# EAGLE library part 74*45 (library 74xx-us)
BCD to decimal DECODER/DRIVER

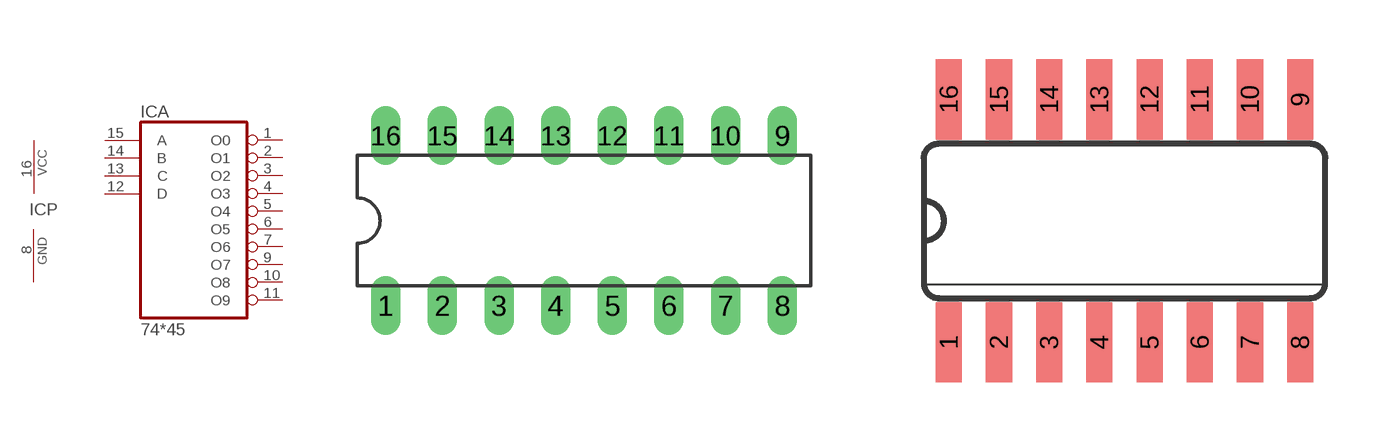
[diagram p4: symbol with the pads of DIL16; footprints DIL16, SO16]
Designator prefix IC; gates A=7445 P=PWRN

## 7445N  [DIL16]
1  A:O0  oc
2  A:O1  oc
3  A:O2  oc
4  A:O3  oc
5  A:O4  oc
6  A:O5  oc
7  A:O6  oc
8  P:GND  pwr
9  A:O7  oc
10  A:O8  oc
11  A:O9  oc
12  A:D  in
13  A:C  in
14  A:B  in
15  A:A  in
16  P:VCC  pwr

## 7445D  [SO16]
Pads as for DIL16

## Footprint DIL16 (pad centres in mm)
Dual In Line Package
drill 0.813 long: 1 -8.89,-3.81; 2 -6.35,-3.81; 3 -3.81,-3.81; 4 -1.27,-3.81; 5 1.27,-3.81; 6 3.81,-3.81; 7 6.35,-3.81; 8 8.89,-3.81; 9 8.89,3.81; 10 6.35,3.81; 11 3.81,3.81; 12 1.27,3.81; 13 -1.27,3.81; 14 -3.81,3.81; 15 -6.35,3.81; 16 -8.89,3.81

## Footprint SO16 (pad centres in mm)
Small Outline package 150 mil
smd 0.66 x 2.032: 1 -4.445,-3.073; 2 -3.175,-3.073; 3 -1.905,-3.073; 4 -0.635,-3.073; 5 0.635,-3.073; 6 1.905,-3.073; 7 3.175,-3.073; 8 4.445,-3.073; 9 4.445,3.073; 10 3.175,3.073; 11 1.905,3.073; 12 0.635,3.073; 13 -0.635,3.073; 14 -1.905,3.073; 15 -3.175,3.073; 16 -4.445,3.073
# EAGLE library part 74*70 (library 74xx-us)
AND gated J-K positive edge triggered FLIP FLOP, preset and clear

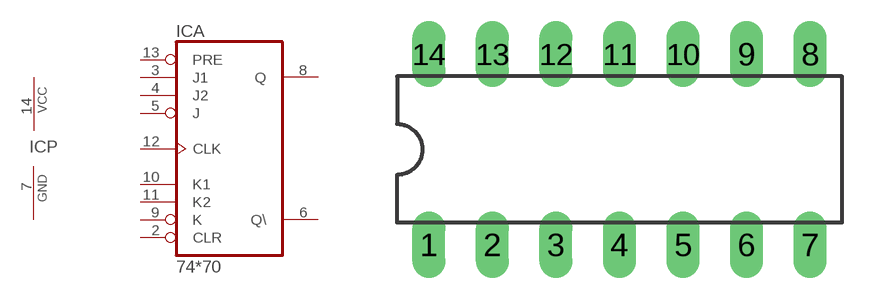
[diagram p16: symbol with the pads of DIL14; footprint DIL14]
Designator prefix IC; gates A=7470 P=PWRN

## 7470N  [DIL14]
2  A:CLR  in
3  A:J1  in
4  A:J2  in
5  A:J  in
6  A:Q\  out
7  P:GND  pwr
8  A:Q  out
9  A:K  in
10  A:K1  in
11  A:K2  in
12  A:CLK  in
13  A:PRE  in
14  P:VCC  pwr

## Footprint DIL14 (pad centres in mm)
Dual In Line Package
drill 0.813 long: 1 -7.62,-3.81; 2 -5.08,-3.81; 3 -2.54,-3.81; 4 0,-3.81; 5 2.54,-3.81; 6 5.08,-3.81; 7 7.62,-3.81; 8 7.62,3.81; 9 5.08,3.81; 10 2.54,3.81; 11 0,3.81; 12 -2.54,3.81; 13 -5.08,3.81; 14 -7.62,3.81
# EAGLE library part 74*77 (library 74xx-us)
4-bit D LATCH

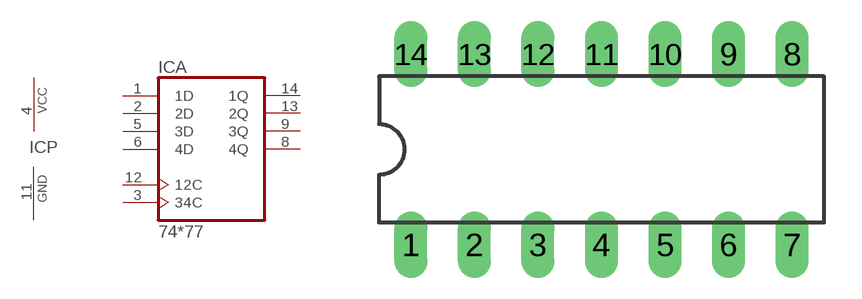
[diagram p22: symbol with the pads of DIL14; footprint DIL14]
Designator prefix IC; gates A=7477 P=PWRN

## 7477N  [DIL14]
1  A:1D  in
2  A:2D  in
3  A:34C  in
4  P:VCC  pwr
5  A:3D  in
6  A:4D  in
8  A:4Q  out
9  A:3Q  out
11  P:GND  pwr
12  A:12C  in
13  A:2Q  out
14  A:1Q  out

## Footprint DIL14 (pad centres in mm)
Dual In Line Package
drill 0.813 long: 1 -7.62,-3.81; 2 -5.08,-3.81; 3 -2.54,-3.81; 4 0,-3.81; 5 2.54,-3.81; 6 5.08,-3.81; 7 7.62,-3.81; 8 7.62,3.81; 9 5.08,3.81; 10 2.54,3.81; 11 0,3.81; 12 -2.54,3.81; 13 -5.08,3.81; 14 -7.62,3.81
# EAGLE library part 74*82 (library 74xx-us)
2-bit binary full ADDER

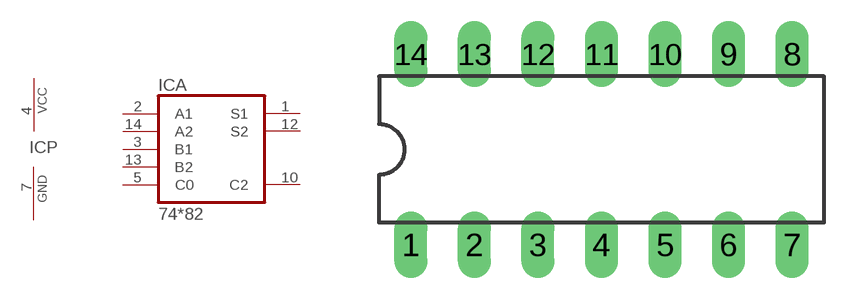
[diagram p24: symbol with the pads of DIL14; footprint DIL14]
Designator prefix IC; gates A=7482 P=PWRN

## 7482N  [DIL14]
1  A:S1  out
2  A:A1  in
3  A:B1  in
4  P:VCC  pwr
5  A:C0  in
7  P:GND  pwr
10  A:C2  out
12  A:S2  out
13  A:B2  in
14  A:A2  in

## Footprint DIL14 (pad centres in mm)
Dual In Line Package
drill 0.813 long: 1 -7.62,-3.81; 2 -5.08,-3.81; 3 -2.54,-3.81; 4 0,-3.81; 5 2.54,-3.81; 6 5.08,-3.81; 7 7.62,-3.81; 8 7.62,3.81; 9 5.08,3.81; 10 2.54,3.81; 11 0,3.81; 12 -2.54,3.81; 13 -5.08,3.81; 14 -7.62,3.81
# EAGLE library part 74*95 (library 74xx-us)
4-bit parallel access SHIFT REGISTER

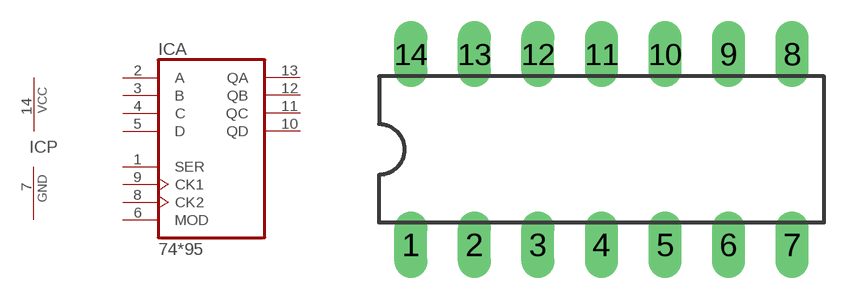
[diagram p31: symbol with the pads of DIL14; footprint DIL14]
Designator prefix IC; gates A=7495 P=PWRN

## 7495N, 74LS95N  [DIL14]
1  A:SER  in
2  A:A  in
3  A:B  in
4  A:C  in
5  A:D  in
6  A:MOD  in
7  P:GND  pwr
8  A:CK2  in
9  A:CK1  in
10  A:QD  out
11  A:QC  out
12  A:QB  out
13  A:QA  out
14  P:VCC  pwr

## Footprint DIL14 (pad centres in mm)
Dual In Line Package
drill 0.813 long: 1 -7.62,-3.81; 2 -5.08,-3.81; 3 -2.54,-3.81; 4 0,-3.81; 5 2.54,-3.81; 6 5.08,-3.81; 7 7.62,-3.81; 8 7.62,3.81; 9 5.08,3.81; 10 2.54,3.81; 11 0,3.81; 12 -2.54,3.81; 13 -5.08,3.81; 14 -7.62,3.81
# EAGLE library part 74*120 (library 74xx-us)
Dual pulse SYNCHRONIZER/DRIVER

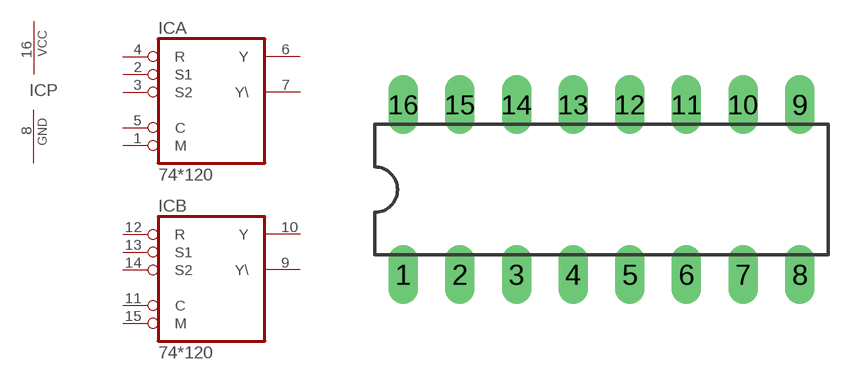
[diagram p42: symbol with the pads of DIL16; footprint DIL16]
Designator prefix IC; gates A=74120 B=74120 P=PWRN

## 74120N  [DIL16]
1  A:M  in
2  A:S1  in
3  A:S2  in
4  A:R  in
5  A:C  in
6  A:Y  out
7  A:Y\  out
8  P:GND  pwr
9  B:Y\  out
10  B:Y  out
11  B:C  in
12  B:R  in
13  B:S1  in
14  B:S2  in
15  B:M  in
16  P:VCC  pwr

## Footprint DIL16 (pad centres in mm)
Dual In Line Package
drill 0.813 long: 1 -8.89,-3.81; 2 -6.35,-3.81; 3 -3.81,-3.81; 4 -1.27,-3.81; 5 1.27,-3.81; 6 3.81,-3.81; 7 6.35,-3.81; 8 8.89,-3.81; 9 8.89,3.81; 10 6.35,3.81; 11 3.81,3.81; 12 1.27,3.81; 13 -1.27,3.81; 14 -3.81,3.81; 15 -6.35,3.81; 16 -8.89,3.81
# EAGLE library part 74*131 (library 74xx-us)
3-line to 8-line DECODER/DEMULTIPLEXER, address register

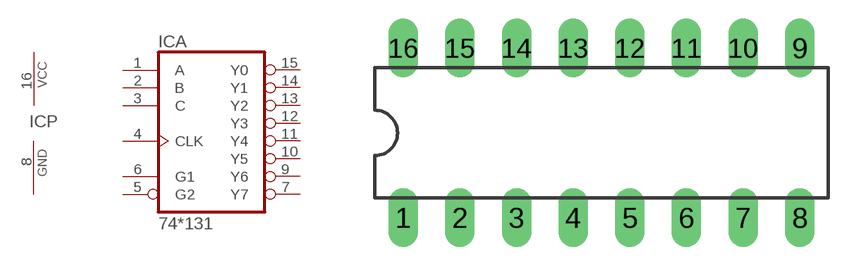
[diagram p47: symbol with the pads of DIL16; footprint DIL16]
Designator prefix IC; gates A=74131 P=PWRN

## 74131N  [DIL16]
1  A:A  in
2  A:B  in
3  A:C  in
4  A:CLK  in
5  A:G2  in
6  A:G1  in
7  A:Y7  out
8  P:GND  pwr
9  A:Y6  out
10  A:Y5  out
11  A:Y4  out
12  A:Y3  out
13  A:Y2  out
14  A:Y1  out
15  A:Y0  out
16  P:VCC  pwr

## Footprint DIL16 (pad centres in mm)
Dual In Line Package
drill 0.813 long: 1 -8.89,-3.81; 2 -6.35,-3.81; 3 -3.81,-3.81; 4 -1.27,-3.81; 5 1.27,-3.81; 6 3.81,-3.81; 7 6.35,-3.81; 8 8.89,-3.81; 9 8.89,3.81; 10 6.35,3.81; 11 3.81,3.81; 12 1.27,3.81; 13 -1.27,3.81; 14 -3.81,3.81; 15 -6.35,3.81; 16 -8.89,3.81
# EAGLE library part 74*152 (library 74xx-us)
Data SELECTOR/MULTIPLEXER

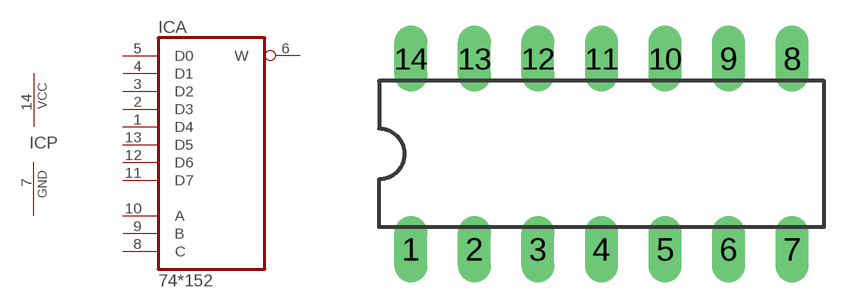
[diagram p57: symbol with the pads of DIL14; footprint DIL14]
Designator prefix IC; gates A=74152 P=PWRN

## 74LS152N  [DIL14]
1  A:D4  in
2  A:D3  in
3  A:D2  in
4  A:D1  in
5  A:D0  in
6  A:W  out
7  P:GND  pwr
8  A:C  in
9  A:B  in
10  A:A  in
11  A:D7  in
12  A:D6  in
13  A:D5  in
14  P:VCC  pwr

## Footprint DIL14 (pad centres in mm)
Dual In Line Package
drill 0.813 long: 1 -7.62,-3.81; 2 -5.08,-3.81; 3 -2.54,-3.81; 4 0,-3.81; 5 2.54,-3.81; 6 5.08,-3.81; 7 7.62,-3.81; 8 7.62,3.81; 9 5.08,3.81; 10 2.54,3.81; 11 0,3.81; 12 -2.54,3.81; 13 -5.08,3.81; 14 -7.62,3.81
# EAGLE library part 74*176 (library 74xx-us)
Presettable decade/binary COUNTER/LATCH

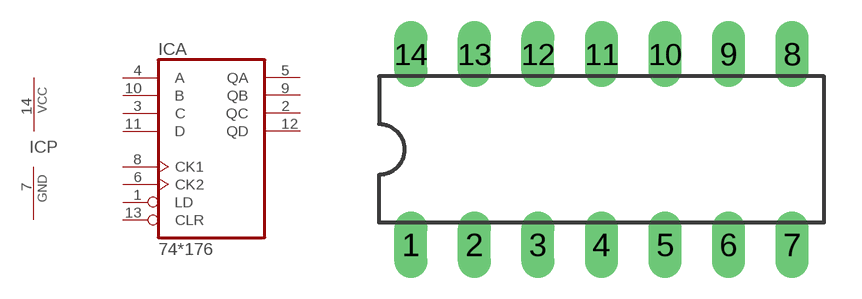
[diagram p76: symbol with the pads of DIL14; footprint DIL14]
Designator prefix IC; gates A=74176 P=PWRN

## 74176N  [DIL14]
1  A:LD  in
2  A:QC  out
3  A:C  in
4  A:A  in
5  A:QA  out
6  A:CK2  in
7  P:GND  pwr
8  A:CK1  in
9  A:QB  out
10  A:B  in
11  A:D  in
12  A:QD  out
13  A:CLR  in
14  P:VCC  pwr

## Footprint DIL14 (pad centres in mm)
Dual In Line Package
drill 0.813 long: 1 -7.62,-3.81; 2 -5.08,-3.81; 3 -2.54,-3.81; 4 0,-3.81; 5 2.54,-3.81; 6 5.08,-3.81; 7 7.62,-3.81; 8 7.62,3.81; 9 5.08,3.81; 10 2.54,3.81; 11 0,3.81; 12 -2.54,3.81; 13 -5.08,3.81; 14 -7.62,3.81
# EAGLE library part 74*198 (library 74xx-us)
8-bit SHIFT REGISTER

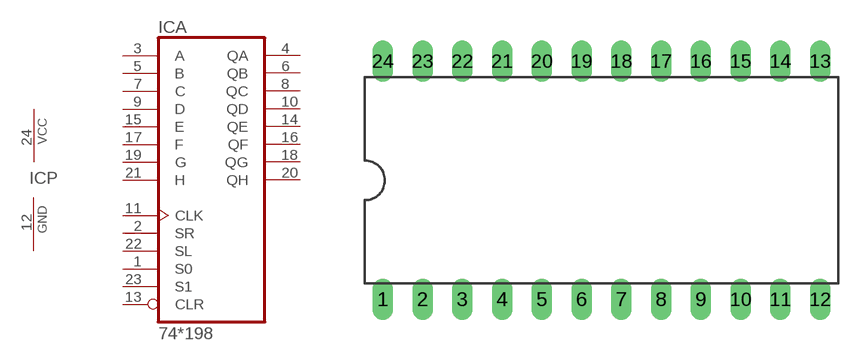
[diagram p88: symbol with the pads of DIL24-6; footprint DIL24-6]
Designator prefix IC; gates A=74198 P=PWRN

## 74198N  [DIL24-6]
1  A:S0  in
2  A:SR  in
3  A:A  in
4  A:QA  out
5  A:B  in
6  A:QB  out
7  A:C  in
8  A:QC  out
9  A:D  in
10  A:QD  out
11  A:CLK  in
12  P:GND  pwr
13  A:CLR  in
14  A:QE  out
15  A:E  in
16  A:QF  out
17  A:F  in
18  A:QG  out
19  A:G  in
20  A:QH  out
21  A:H  in
22  A:SL  in
23  A:S1  in
24  P:VCC  pwr

## Footprint DIL24-6 (pad centres in mm)
Dual In Line Package 0.6 inch
drill 0.813 long: 1 -13.97,-7.62; 2 -11.43,-7.62; 3 -8.89,-7.62; 4 -6.35,-7.62; 5 -3.81,-7.62; 6 -1.27,-7.62; 7 1.27,-7.62; 8 3.81,-7.62; 9 6.35,-7.62; 10 8.89,-7.62; 11 11.43,-7.62; 12 13.97,-7.62; 13 13.97,7.62; 14 11.43,7.62; 15 8.89,7.62; 16 6.35,7.62; 17 3.81,7.62; 18 1.27,7.62; 19 -1.27,7.62; 20 -3.81,7.62; 21 -6.35,7.62; 22 -8.89,7.62; 23 -11.43,7.62; 24 -13.97,7.62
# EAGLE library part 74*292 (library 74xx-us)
Programmable frequency DIVIDER/DIGITAL TIMER

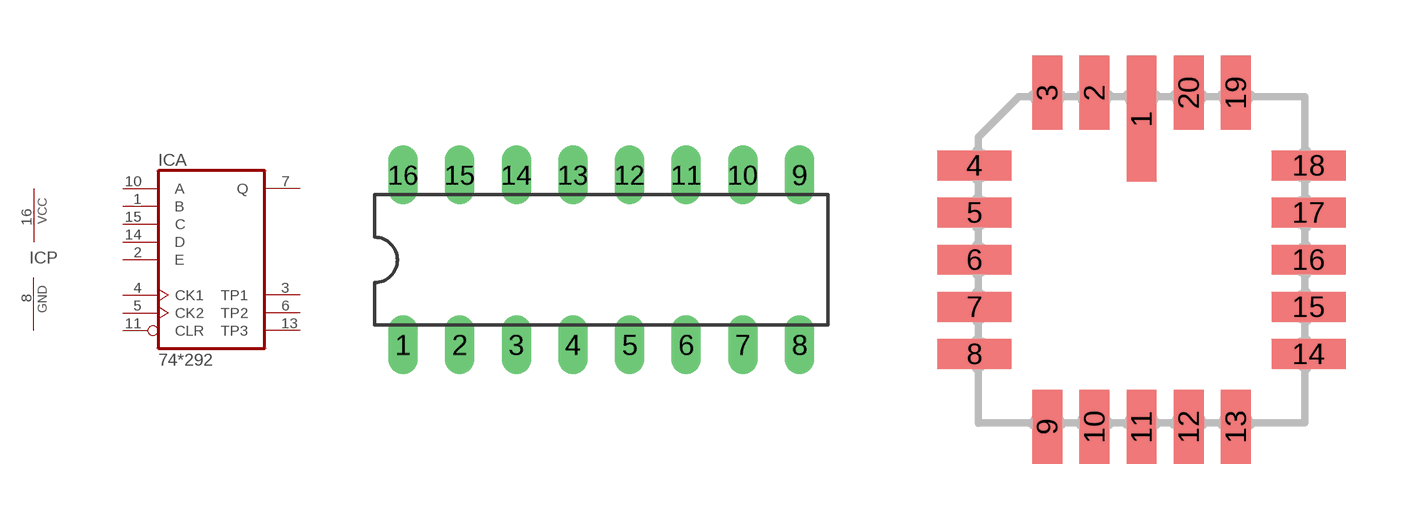
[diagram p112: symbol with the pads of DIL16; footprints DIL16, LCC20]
Designator prefix IC; gates A=74292 P=PWRN

## 74LS292N  [DIL16]
1  A:B  in
2  A:E  in
3  A:TP1  out
4  A:CK1  in
5  A:CK2  in
6  A:TP2  out
7  A:Q  out
8  P:GND  pwr
10  A:A  in
11  A:CLR  in
13  A:TP3  out
14  A:D  in
15  A:C  in
16  P:VCC  pwr

## 74LS292FK  [LCC20]
2  A:B  in
3  A:E  in
4  A:TP1  out
5  A:CK1  in
7  A:CK2  in
8  A:TP2  out
9  A:Q  out
10  P:GND  pwr
13  A:A  in
14  A:CLR  in
17  A:TP3  out
18  A:D  in
19  A:C  in
20  P:VCC  pwr

## Footprint DIL16 (pad centres in mm)
Dual In Line Package
drill 0.813 long: 1 -8.89,-3.81; 2 -6.35,-3.81; 3 -3.81,-3.81; 4 -1.27,-3.81; 5 1.27,-3.81; 6 3.81,-3.81; 7 6.35,-3.81; 8 8.89,-3.81; 9 8.89,3.81; 10 6.35,3.81; 11 3.81,3.81; 12 1.27,3.81; 13 -1.27,3.81; 14 -3.81,3.81; 15 -6.35,3.81; 16 -8.89,3.81

## Footprint LCC20 (pad centres in mm)
Leadless Chip Carrier Ceramic Package
smd 0.8 x 3.4: 1 0,3.8
smd 0.8 x 2: 2 -1.27,4.5; 3 -2.54,4.5; 9 -2.54,-4.5; 10 -1.27,-4.5; 11 0,-4.5; 12 1.27,-4.5; 13 2.54,-4.5; 19 2.54,4.5; 20 1.27,4.5
smd 2 x 0.8: 4 -4.5,2.54; 5 -4.5,1.27; 6 -4.5,0; 7 -4.5,-1.27; 8 -4.5,-2.54; 14 4.5,-2.54; 15 4.5,-1.27; 16 4.5,0; 17 4.5,1.27; 18 4.5,2.54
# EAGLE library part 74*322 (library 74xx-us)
8-bit SHIFT REGISTER

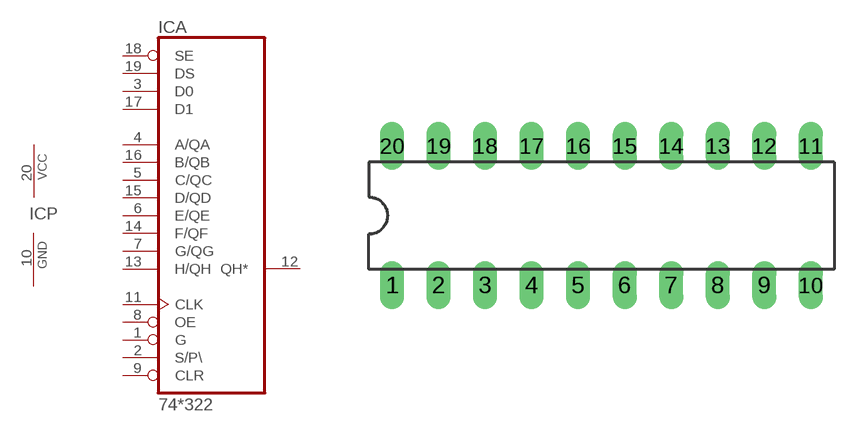
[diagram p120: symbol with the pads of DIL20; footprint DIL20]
Designator prefix IC; gates A=74322 P=PWRN

## 74322N  [DIL20]
1  A:G  in
2  A:S/P\  in
3  A:D0  in
4  A:A/QA
5  A:C/QC  in
6  A:E/QE  in
7  A:G/QG
8  A:OE  in
9  A:CLR  in
10  P:GND  pwr
11  A:CLK  in
12  A:QH*  hiz
13  A:H/QH
14  A:F/QF
15  A:D/QD  in
16  A:B/QB
17  A:D1  in
18  A:SE  in
19  A:DS  in
20  P:VCC  pwr

## Footprint DIL20 (pad centres in mm)
Dual In Line Package
drill 0.813 long: 1 -11.43,-3.81; 2 -8.89,-3.81; 3 -6.35,-3.81; 4 -3.81,-3.81; 5 -1.27,-3.81; 6 1.27,-3.81; 7 3.81,-3.81; 8 6.35,-3.81; 9 8.89,-3.81; 10 11.43,-3.81; 11 11.43,3.81; 12 8.89,3.81; 13 6.35,3.81; 14 3.81,3.81; 15 1.27,3.81; 16 -1.27,3.81; 17 -3.81,3.81; 18 -6.35,3.81; 19 -8.89,3.81; 20 -11.43,3.81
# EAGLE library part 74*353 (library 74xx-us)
Dual 4-to 1 line data SELECTOR/MULTIPLEXER, 3-state

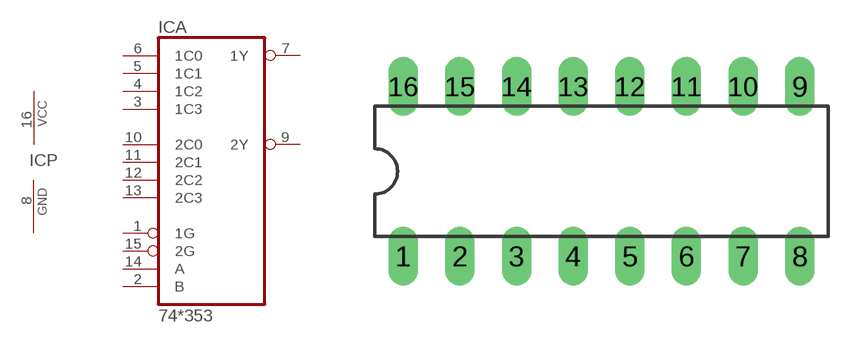
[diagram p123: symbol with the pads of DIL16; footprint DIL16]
Designator prefix IC; gates A=74353 P=PWRN

## 74353N  [DIL16]
1  A:1G  in
2  A:B  in
3  A:1C3  in
4  A:1C2  in
5  A:1C1  in
6  A:1C0  in
7  A:1Y  hiz
8  P:GND  pwr
9  A:2Y  hiz
10  A:2C0  in
11  A:2C1  in
12  A:2C2  in
13  A:2C3  in
14  A:A  in
15  A:2G  in
16  P:VCC  pwr

## Footprint DIL16 (pad centres in mm)
Dual In Line Package
drill 0.813 long: 1 -8.89,-3.81; 2 -6.35,-3.81; 3 -3.81,-3.81; 4 -1.27,-3.81; 5 1.27,-3.81; 6 3.81,-3.81; 7 6.35,-3.81; 8 8.89,-3.81; 9 8.89,3.81; 10 6.35,3.81; 11 3.81,3.81; 12 1.27,3.81; 13 -1.27,3.81; 14 -3.81,3.81; 15 -6.35,3.81; 16 -8.89,3.81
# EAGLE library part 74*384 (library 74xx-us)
8-bit by 1 twos-complement MULTIPLIER'

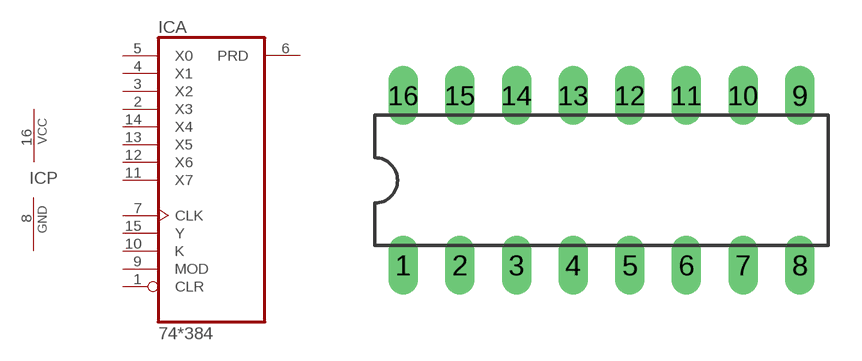
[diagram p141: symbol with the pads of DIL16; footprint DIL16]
Designator prefix IC; gates A=74384 P=PWRN

## 74384N  [DIL16]
1  A:CLR  in
2  A:X3  in
3  A:X2  in
4  A:X1  in
5  A:X0  in
6  A:PRD  out
7  A:CLK  in
8  P:GND  pwr
9  A:MOD  in
10  A:K  in
11  A:X7  in
12  A:X6  in
13  A:X5  in
14  A:X4  in
15  A:Y  in
16  P:VCC  pwr

## Footprint DIL16 (pad centres in mm)
Dual In Line Package
drill 0.813 long: 1 -8.89,-3.81; 2 -6.35,-3.81; 3 -3.81,-3.81; 4 -1.27,-3.81; 5 1.27,-3.81; 6 3.81,-3.81; 7 6.35,-3.81; 8 8.89,-3.81; 9 8.89,3.81; 10 6.35,3.81; 11 3.81,3.81; 12 1.27,3.81; 13 -1.27,3.81; 14 -3.81,3.81; 15 -6.35,3.81; 16 -8.89,3.81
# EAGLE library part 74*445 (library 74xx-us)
BCD to decimal DECODER/DRIVER

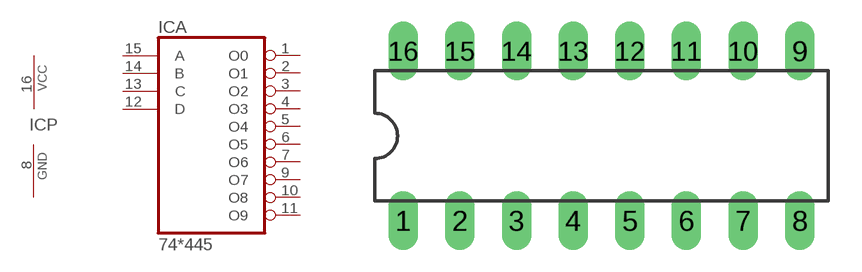
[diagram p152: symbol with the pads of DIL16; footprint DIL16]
Designator prefix IC; gates A=74445 P=PWRN

## 74445N  [DIL16]
1  A:O0  out
2  A:O1  out
3  A:O2  out
4  A:O3  out
5  A:O4  out
6  A:O5  out
7  A:O6  out
8  P:GND  pwr
9  A:O7  out
10  A:O8  out
11  A:O9  out
12  A:D  in
13  A:C  in
14  A:B  in
15  A:A  in
16  P:VCC  pwr

## Footprint DIL16 (pad centres in mm)
Dual In Line Package
drill 0.813 long: 1 -8.89,-3.81; 2 -6.35,-3.81; 3 -3.81,-3.81; 4 -1.27,-3.81; 5 1.27,-3.81; 6 3.81,-3.81; 7 6.35,-3.81; 8 8.89,-3.81; 9 8.89,3.81; 10 6.35,3.81; 11 3.81,3.81; 12 1.27,3.81; 13 -1.27,3.81; 14 -3.81,3.81; 15 -6.35,3.81; 16 -8.89,3.81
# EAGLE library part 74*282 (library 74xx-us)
LOOK AHEAD CARRY GENERATOR

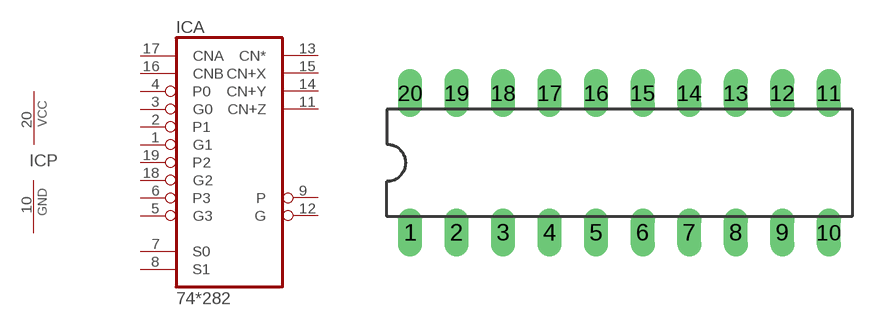
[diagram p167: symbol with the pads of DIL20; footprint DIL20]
Designator prefix IC; gates A=74282 P=PWRN

## 74AS282N  [DIL20]
1  A:G1  in
2  A:P1  in
3  A:G0  in
4  A:P0  in
5  A:G3  in
6  A:P3  in
7  A:S0  in
8  A:S1  in
9  A:P  out
10  P:GND  pwr
11  A:CN+Z  out
12  A:G  out
13  A:CN*  out
14  A:CN+Y  out
15  A:CN+X  out
16  A:CNB  in
17  A:CNA  in
18  A:G2  in
19  A:P2  in
20  P:VCC  pwr

## Footprint DIL20 (pad centres in mm)
Dual In Line Package
drill 0.813 long: 1 -11.43,-3.81; 2 -8.89,-3.81; 3 -6.35,-3.81; 4 -3.81,-3.81; 5 -1.27,-3.81; 6 1.27,-3.81; 7 3.81,-3.81; 8 6.35,-3.81; 9 8.89,-3.81; 10 11.43,-3.81; 11 11.43,3.81; 12 8.89,3.81; 13 6.35,3.81; 14 3.81,3.81; 15 1.27,3.81; 16 -1.27,3.81; 17 -3.81,3.81; 18 -6.35,3.81; 19 -8.89,3.81; 20 -11.43,3.81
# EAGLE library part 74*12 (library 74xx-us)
Triple 3-input NAND gate, open collector

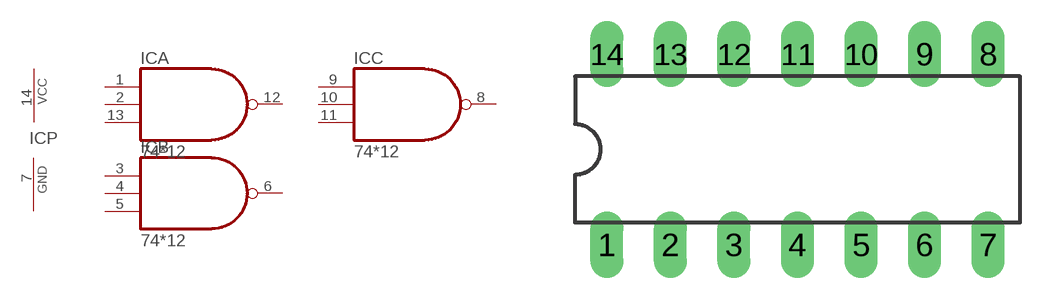
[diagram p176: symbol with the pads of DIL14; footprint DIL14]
Designator prefix IC; gates A=7412 B=7412 C=7412 P=PWRN

## 7412N, 74LS12N  [DIL14]
1  A:I0  in
2  A:I1  in
3  B:I0  in
4  B:I1  in
5  B:I2  in
6  B:O  oc
7  P:GND  pwr
8  C:O  oc
9  C:I0  in
10  C:I1  in
11  C:I2  in
12  A:O  oc
13  A:I2  in
14  P:VCC  pwr

## Footprint DIL14 (pad centres in mm)
Dual In Line Package
drill 0.813 long: 1 -7.62,-3.81; 2 -5.08,-3.81; 3 -2.54,-3.81; 4 0,-3.81; 5 2.54,-3.81; 6 5.08,-3.81; 7 7.62,-3.81; 8 7.62,3.81; 9 5.08,3.81; 10 2.54,3.81; 11 0,3.81; 12 -2.54,3.81; 13 -5.08,3.81; 14 -7.62,3.81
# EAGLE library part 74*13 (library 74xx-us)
Dual 4-input NAND schmitt trigger

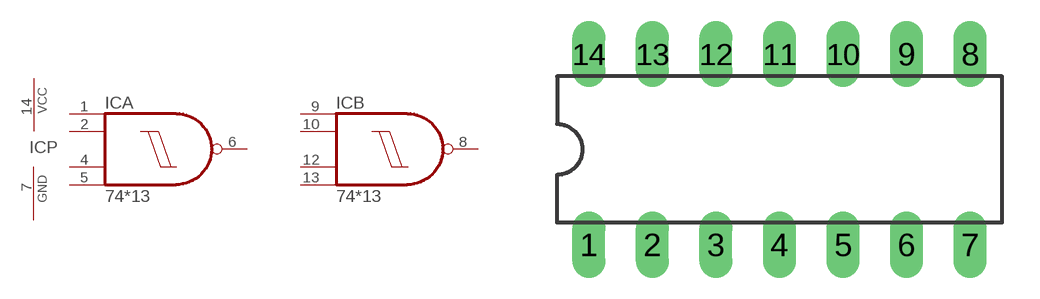
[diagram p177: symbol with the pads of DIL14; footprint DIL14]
Designator prefix IC; gates A=7413 B=7413 P=PWRN

## 7413N, 74LS13N  [DIL14]
1  A:I0  in
2  A:I1  in
4  A:I2  in
5  A:I3  in
6  A:O  out
7  P:GND  pwr
8  B:O  out
9  B:I0  in
10  B:I1  in
12  B:I2  in
13  B:I3  in
14  P:VCC  pwr

## Footprint DIL14 (pad centres in mm)
Dual In Line Package
drill 0.813 long: 1 -7.62,-3.81; 2 -5.08,-3.81; 3 -2.54,-3.81; 4 0,-3.81; 5 2.54,-3.81; 6 5.08,-3.81; 7 7.62,-3.81; 8 7.62,3.81; 9 5.08,3.81; 10 2.54,3.81; 11 0,3.81; 12 -2.54,3.81; 13 -5.08,3.81; 14 -7.62,3.81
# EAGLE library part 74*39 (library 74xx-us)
Quad 2-input NAND buffer, open collector

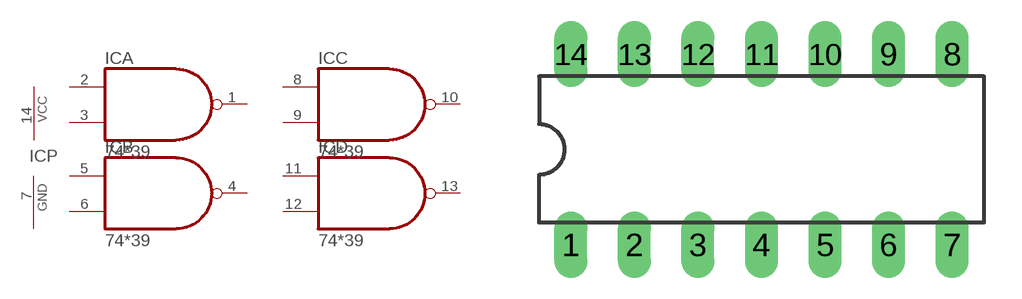
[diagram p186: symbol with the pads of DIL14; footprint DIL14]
Designator prefix IC; gates A=7439 B=7439 C=7439 D=7439 P=PWRN

## 7439N  [DIL14]
1  A:O  oc
2  A:I0  in
3  A:I1  in
4  B:O  oc
5  B:I0  in
6  B:I1  in
7  P:GND  pwr
8  C:I0  in
9  C:I1  in
10  C:O  oc
11  D:I0  in
12  D:I1  in
13  D:O  oc
14  P:VCC  pwr

## Footprint DIL14 (pad centres in mm)
Dual In Line Package
drill 0.813 long: 1 -7.62,-3.81; 2 -5.08,-3.81; 3 -2.54,-3.81; 4 0,-3.81; 5 2.54,-3.81; 6 5.08,-3.81; 7 7.62,-3.81; 8 7.62,3.81; 9 5.08,3.81; 10 2.54,3.81; 11 0,3.81; 12 -2.54,3.81; 13 -5.08,3.81; 14 -7.62,3.81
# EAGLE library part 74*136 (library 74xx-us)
Quad EXCLUSIV-OR/NOR (XOR/NOR) gate, open collector

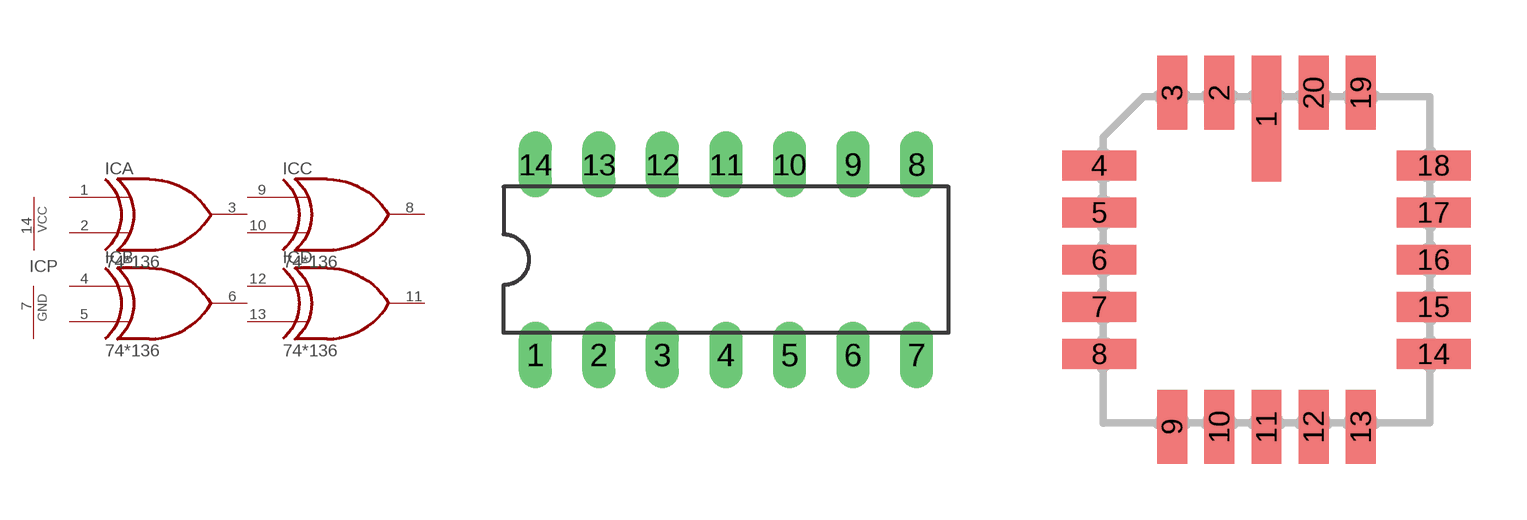
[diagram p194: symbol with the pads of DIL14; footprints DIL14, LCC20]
Designator prefix IC; gates A=74136 B=74136 C=74136 D=74136 P=PWRN

## 74LS136N  [DIL14]
1  A:I0  in
2  A:I1  in
3  A:O  oc
4  B:I0  in
5  B:I1  in
6  B:O  oc
7  P:GND  pwr
8  C:O  oc
9  C:I0  in
10  C:I1  in
11  D:O  oc
12  D:I0  in
13  D:I1  in
14  P:VCC  pwr

## 74LS136D  [DIL14]
Pads as for DIL14

## 74LS136FK  [LCC20]
2  A:I0  in
3  A:I1  in
4  A:O  oc
6  B:I0  in
8  B:I1  in
9  B:O  oc
10  P:GND  pwr
12  C:O  oc
13  C:I0  in
14  C:I1  in
16  D:O  oc
18  D:I0  in
19  D:I1  in
20  P:VCC  pwr

## Footprint DIL14 (pad centres in mm)
Dual In Line Package
drill 0.813 long: 1 -7.62,-3.81; 2 -5.08,-3.81; 3 -2.54,-3.81; 4 0,-3.81; 5 2.54,-3.81; 6 5.08,-3.81; 7 7.62,-3.81; 8 7.62,3.81; 9 5.08,3.81; 10 2.54,3.81; 11 0,3.81; 12 -2.54,3.81; 13 -5.08,3.81; 14 -7.62,3.81

## Footprint LCC20 (pad centres in mm)
Leadless Chip Carrier Ceramic Package
smd 0.8 x 3.4: 1 0,3.8
smd 0.8 x 2: 2 -1.27,4.5; 3 -2.54,4.5; 9 -2.54,-4.5; 10 -1.27,-4.5; 11 0,-4.5; 12 1.27,-4.5; 13 2.54,-4.5; 19 2.54,4.5; 20 1.27,4.5
smd 2 x 0.8: 4 -4.5,2.54; 5 -4.5,1.27; 6 -4.5,0; 7 -4.5,-1.27; 8 -4.5,-2.54; 14 4.5,-2.54; 15 4.5,-1.27; 16 4.5,0; 17 4.5,1.27; 18 4.5,2.54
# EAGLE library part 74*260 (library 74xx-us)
Dual 5-input positive NOR gate

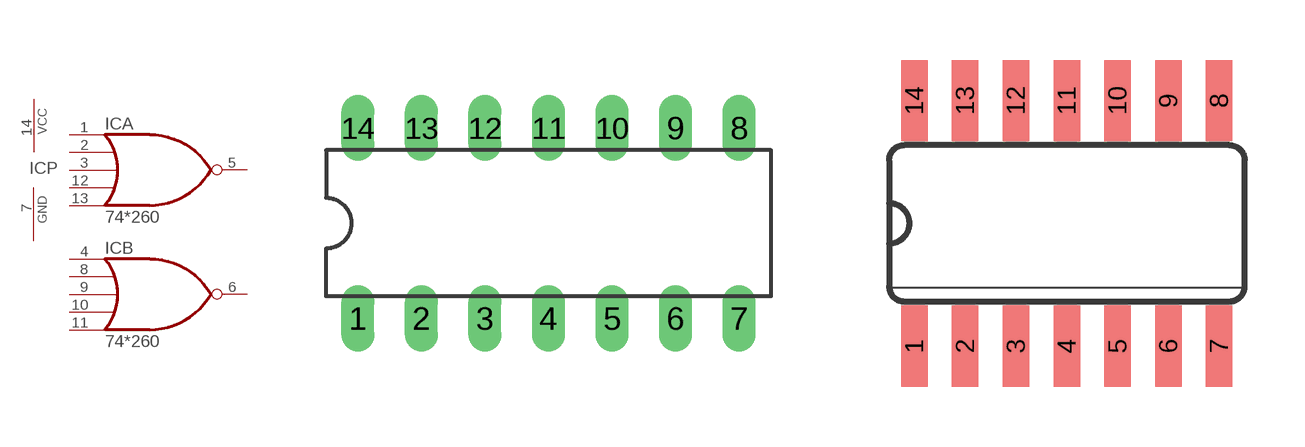
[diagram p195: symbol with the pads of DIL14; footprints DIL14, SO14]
Designator prefix IC; gates A=74260 B=74260 P=PWRN

## 74S260N  [DIL14]
1  A:I0  in
2  A:I1  in
3  A:I2  in
4  B:I0  in
5  A:O  out
6  B:O  out
7  P:GND  pwr
8  B:I1  in
9  B:I2  in
10  B:I3  in
11  B:I4  in
12  A:I3  in
13  A:I4  in
14  P:VCC  pwr

## 74S260D  [SO14]
Pads as for DIL14

## 74S260FK  [LCC20]
2  A:I0  in
3  A:I1  in
4  A:I2  in
6  B:I0  in
8  A:O  out
9  B:O  out
10  P:GND  pwr
12  B:I1  in
13  B:I2  in
14  B:I3  in
16  B:I4  in
18  A:I3  in
19  A:I4  in
20  P:VCC  pwr

## Footprint DIL14 (pad centres in mm)
Dual In Line Package
drill 0.813 long: 1 -7.62,-3.81; 2 -5.08,-3.81; 3 -2.54,-3.81; 4 0,-3.81; 5 2.54,-3.81; 6 5.08,-3.81; 7 7.62,-3.81; 8 7.62,3.81; 9 5.08,3.81; 10 2.54,3.81; 11 0,3.81; 12 -2.54,3.81; 13 -5.08,3.81; 14 -7.62,3.81

## Footprint SO14 (pad centres in mm)
Small Outline package 150 mil
smd 0.66 x 2.032: 1 -3.81,-3.073; 2 -2.54,-3.073; 3 -1.27,-3.073; 4 0,-3.073; 5 1.27,-3.073; 6 2.54,-3.073; 7 3.81,-3.073; 8 3.81,3.073; 9 2.54,3.073; 10 1.27,3.073; 11 0,3.073; 12 -1.27,3.073; 13 -2.54,3.073; 14 -3.81,3.073

## Footprint LCC20 (pad centres in mm)
Leadless Chip Carrier Ceramic Package
smd 0.8 x 3.4: 1 0,3.8
smd 0.8 x 2: 2 -1.27,4.5; 3 -2.54,4.5; 9 -2.54,-4.5; 10 -1.27,-4.5; 11 0,-4.5; 12 1.27,-4.5; 13 2.54,-4.5; 19 2.54,4.5; 20 1.27,4.5
smd 2 x 0.8: 4 -4.5,2.54; 5 -4.5,1.27; 6 -4.5,0; 7 -4.5,-1.27; 8 -4.5,-2.54; 14 4.5,-2.54; 15 4.5,-1.27; 16 4.5,0; 17 4.5,1.27; 18 4.5,2.54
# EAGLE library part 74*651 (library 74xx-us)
8-bit BUS TRANSCEIVER and REGISTER

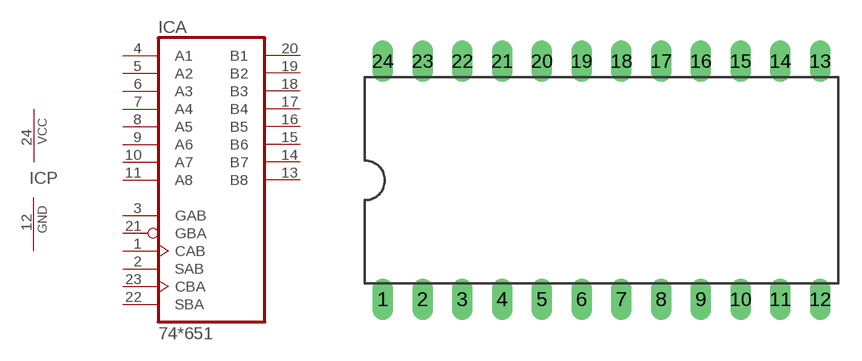
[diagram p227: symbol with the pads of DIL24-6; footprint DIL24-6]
Designator prefix IC; gates A=74651 P=PWRN

## 74AS651NT, 74LS651NT  [DIL24-6]
1  A:CAB  in
2  A:SAB  in
3  A:GAB  in
4  A:A1
5  A:A2
6  A:A3
7  A:A4
8  A:A5
9  A:A6
10  A:A7
11  A:A8
12  P:GND  pwr
13  A:B8
14  A:B7
15  A:B6
16  A:B5
17  A:B4
18  A:B3
19  A:B2
20  A:B1
21  A:GBA  in
22  A:SBA  in
23  A:CBA  in
24  P:VCC  pwr

## Footprint DIL24-6 (pad centres in mm)
Dual In Line Package 0.6 inch
drill 0.813 long: 1 -13.97,-7.62; 2 -11.43,-7.62; 3 -8.89,-7.62; 4 -6.35,-7.62; 5 -3.81,-7.62; 6 -1.27,-7.62; 7 1.27,-7.62; 8 3.81,-7.62; 9 6.35,-7.62; 10 8.89,-7.62; 11 11.43,-7.62; 12 13.97,-7.62; 13 13.97,7.62; 14 11.43,7.62; 15 8.89,7.62; 16 6.35,7.62; 17 3.81,7.62; 18 1.27,7.62; 19 -1.27,7.62; 20 -3.81,7.62; 21 -6.35,7.62; 22 -8.89,7.62; 23 -11.43,7.62; 24 -13.97,7.62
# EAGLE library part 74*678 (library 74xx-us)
16-bit address COMPARATOR, latch

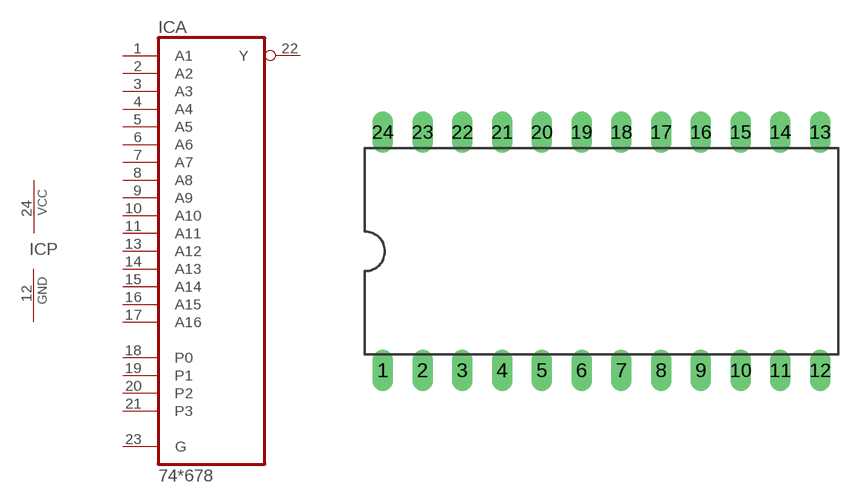
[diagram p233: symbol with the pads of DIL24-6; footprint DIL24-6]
Designator prefix IC; gates A=74678 P=PWRN

## 74ALS678NT  [DIL24-6]
1  A:A1  in
2  A:A2  in
3  A:A3  in
4  A:A4  in
5  A:A5  in
6  A:A6  in
7  A:A7  in
8  A:A8  in
9  A:A9  in
10  A:A10  in
11  A:A11  in
12  P:GND  pwr
13  A:A12  in
14  A:A13  in
15  A:A14  in
16  A:A15  in
17  A:A16  in
18  A:P0  in
19  A:P1  in
20  A:P2  in
21  A:P3  in
22  A:Y  out
23  A:G  in
24  P:VCC  pwr

## Footprint DIL24-6 (pad centres in mm)
Dual In Line Package 0.6 inch
drill 0.813 long: 1 -13.97,-7.62; 2 -11.43,-7.62; 3 -8.89,-7.62; 4 -6.35,-7.62; 5 -3.81,-7.62; 6 -1.27,-7.62; 7 1.27,-7.62; 8 3.81,-7.62; 9 6.35,-7.62; 10 8.89,-7.62; 11 11.43,-7.62; 12 13.97,-7.62; 13 13.97,7.62; 14 11.43,7.62; 15 8.89,7.62; 16 6.35,7.62; 17 3.81,7.62; 18 1.27,7.62; 19 -1.27,7.62; 20 -3.81,7.62; 21 -6.35,7.62; 22 -8.89,7.62; 23 -11.43,7.62; 24 -13.97,7.62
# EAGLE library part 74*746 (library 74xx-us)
Octal BUS DRIVER, inverting, pull-up resistors

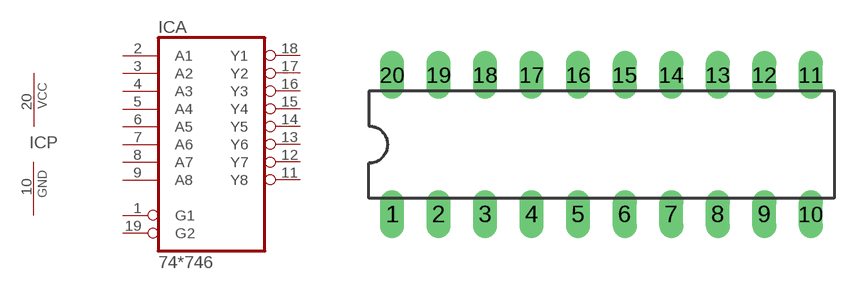
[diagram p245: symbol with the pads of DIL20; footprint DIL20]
Designator prefix IC; gates A=74746 P=PWRN

## 74ALS746N  [DIL20]
1  A:G1  in
2  A:A1  in
3  A:A2  in
4  A:A3  in
5  A:A4  in
6  A:A5  in
7  A:A6  in
8  A:A7  in
9  A:A8  in
10  P:GND  pwr
11  A:Y8  out
12  A:Y7  out
13  A:Y6  out
14  A:Y5  out
15  A:Y4  out
16  A:Y3  out
17  A:Y2  out
18  A:Y1  out
19  A:G2  in
20  P:VCC  pwr

## Footprint DIL20 (pad centres in mm)
Dual In Line Package
drill 0.813 long: 1 -11.43,-3.81; 2 -8.89,-3.81; 3 -6.35,-3.81; 4 -3.81,-3.81; 5 -1.27,-3.81; 6 1.27,-3.81; 7 3.81,-3.81; 8 6.35,-3.81; 9 8.89,-3.81; 10 11.43,-3.81; 11 11.43,3.81; 12 8.89,3.81; 13 6.35,3.81; 14 3.81,3.81; 15 1.27,3.81; 16 -1.27,3.81; 17 -3.81,3.81; 18 -6.35,3.81; 19 -8.89,3.81; 20 -11.43,3.81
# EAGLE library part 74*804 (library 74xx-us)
Hex NAND driver

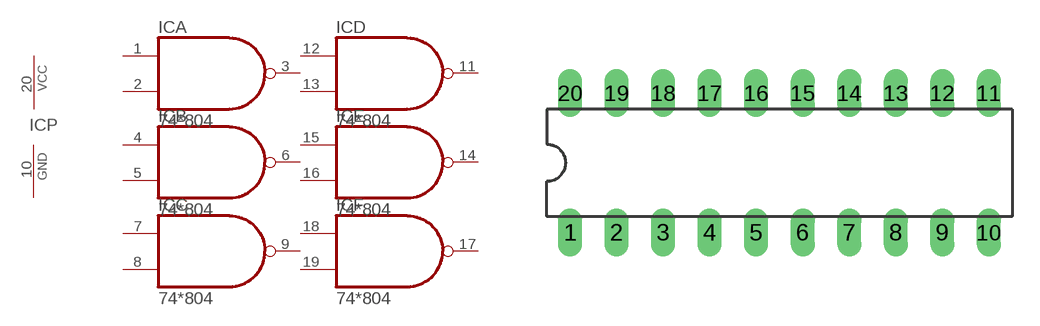
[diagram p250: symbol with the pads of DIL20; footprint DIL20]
Designator prefix IC; gates A=74804 B=74804 C=74804 D=74804 E=74804 F=74804 P=PWRN

## 74ALS804N, 74AS804N  [DIL20]
1  A:I0  in
2  A:I1  in
3  A:O  out
4  B:I0  in
5  B:I1  in
6  B:O  out
7  C:I0  in
8  C:I1  in
9  C:O  out
10  P:GND  pwr
11  D:O  out
12  D:I0  in
13  D:I1  in
14  E:O  out
15  E:I0  in
16  E:I1  in
17  F:O  out
18  F:I0  in
19  F:I1  in
20  P:VCC  pwr

## Footprint DIL20 (pad centres in mm)
Dual In Line Package
drill 0.813 long: 1 -11.43,-3.81; 2 -8.89,-3.81; 3 -6.35,-3.81; 4 -3.81,-3.81; 5 -1.27,-3.81; 6 1.27,-3.81; 7 3.81,-3.81; 8 6.35,-3.81; 9 8.89,-3.81; 10 11.43,-3.81; 11 11.43,3.81; 12 8.89,3.81; 13 6.35,3.81; 14 3.81,3.81; 15 1.27,3.81; 16 -1.27,3.81; 17 -3.81,3.81; 18 -6.35,3.81; 19 -8.89,3.81; 20 -11.43,3.81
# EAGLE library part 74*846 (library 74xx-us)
8-bit inverting bus interface LATCH

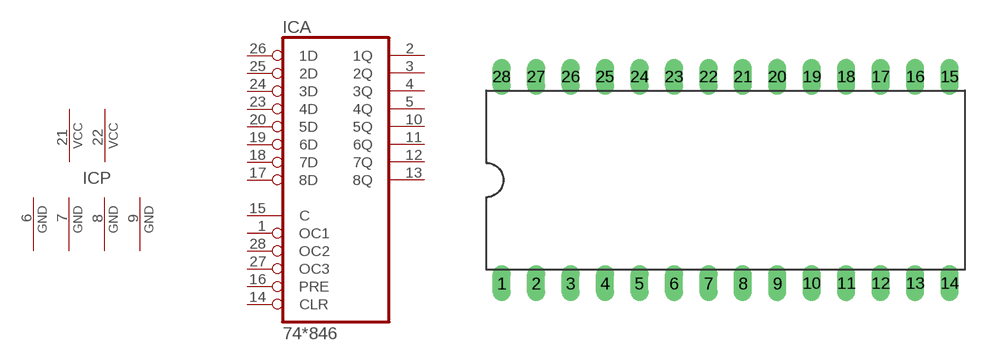
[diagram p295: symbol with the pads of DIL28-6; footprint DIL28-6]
Designator prefix IC; gates A=74846 P=2PWR4GND

## 74ALS846NT, 74AS846NT  [DIL28-6]
1  A:OC1  in
2  A:1Q  hiz
3  A:2Q  hiz
4  A:3Q  hiz
5  A:4Q  hiz
6  P:GND  pwr
7  P:GND  pwr
8  P:GND  pwr
9  P:GND  pwr
10  A:5Q  hiz
11  A:6Q  hiz
12  A:7Q  hiz
13  A:8Q  hiz
14  A:CLR  in
15  A:C  in
16  A:PRE  in
17  A:8D  in
18  A:7D  in
19  A:6D  in
20  A:5D  in
21  P:VCC  pwr
22  P:VCC  pwr
23  A:4D  in
24  A:3D  in
25  A:2D  in
26  A:1D  in
27  A:OC3  in
28  A:OC2  in

## Footprint DIL28-6 (pad centres in mm)
Dual In Line Package 0.6 inch
drill 0.813 long: 1 -16.51,-7.62; 2 -13.97,-7.62; 3 -11.43,-7.62; 4 -8.89,-7.62; 5 -6.35,-7.62; 6 -3.81,-7.62; 7 -1.27,-7.62; 8 1.27,-7.62; 9 3.81,-7.62; 10 6.35,-7.62; 11 8.89,-7.62; 12 11.43,-7.62; 13 13.97,-7.62; 14 16.51,-7.62; 15 16.51,7.62; 16 13.97,7.62; 17 11.43,7.62; 18 8.89,7.62; 19 6.35,7.62; 20 3.81,7.62; 21 1.27,7.62; 22 -1.27,7.62; 23 -3.81,7.62; 24 -6.35,7.62; 25 -8.89,7.62; 26 -11.43,7.62; 27 -13.97,7.62; 28 -16.51,7.62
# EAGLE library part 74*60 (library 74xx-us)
Dual 4-input EXPANDER

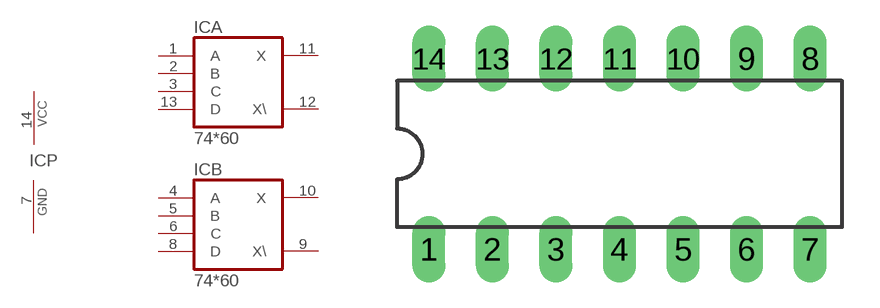
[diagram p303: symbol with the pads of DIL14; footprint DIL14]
Designator prefix IC; gates A=7460 B=7460 P=PWRN

## 7460N  [DIL14]
1  A:A  in
2  A:B  in
3  A:C  in
4  B:A  in
5  B:B  in
6  B:C  in
7  P:GND  pwr
8  B:D  in
9  B:X\  out
10  B:X  out
11  A:X  out
12  A:X\  out
13  A:D  in
14  P:VCC  pwr

## Footprint DIL14 (pad centres in mm)
Dual In Line Package
drill 0.813 long: 1 -7.62,-3.81; 2 -5.08,-3.81; 3 -2.54,-3.81; 4 0,-3.81; 5 2.54,-3.81; 6 5.08,-3.81; 7 7.62,-3.81; 8 7.62,3.81; 9 5.08,3.81; 10 2.54,3.81; 11 0,3.81; 12 -2.54,3.81; 13 -5.08,3.81; 14 -7.62,3.81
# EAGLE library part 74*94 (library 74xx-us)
4-bit SHIFT REGISTER, parallel NOR inputs, serial output

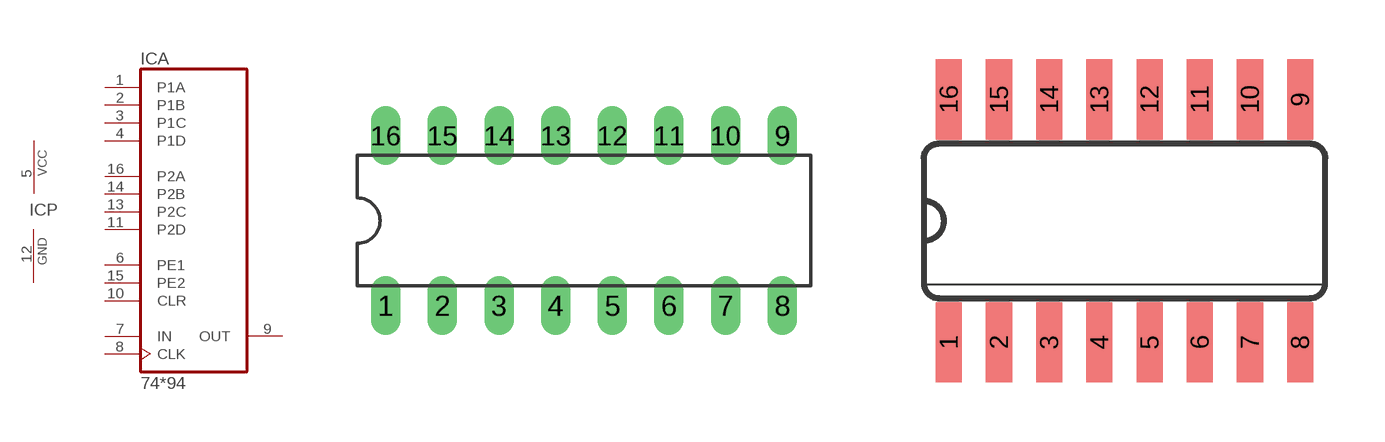
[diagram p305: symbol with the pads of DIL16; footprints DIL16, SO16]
Designator prefix IC; gates A=7494 P=PWRN

## 7494N  [DIL16]
1  A:P1A  in
2  A:P1B  in
3  A:P1C  in
4  A:P1D  in
5  P:VCC  pwr
6  A:PE1  in
7  A:IN  in
8  A:CLK  in
9  A:OUT  out
10  A:CLR  in
11  A:P2D  in
12  P:GND  pwr
13  A:P2C  in
14  A:P2B  in
15  A:PE2  in
16  A:P2A  in

## 7494J  [SO16]
Pads as for DIL16

## Footprint DIL16 (pad centres in mm)
Dual In Line Package
drill 0.813 long: 1 -8.89,-3.81; 2 -6.35,-3.81; 3 -3.81,-3.81; 4 -1.27,-3.81; 5 1.27,-3.81; 6 3.81,-3.81; 7 6.35,-3.81; 8 8.89,-3.81; 9 8.89,3.81; 10 6.35,3.81; 11 3.81,3.81; 12 1.27,3.81; 13 -1.27,3.81; 14 -3.81,3.81; 15 -6.35,3.81; 16 -8.89,3.81

## Footprint SO16 (pad centres in mm)
Small Outline package 150 mil
smd 0.66 x 2.032: 1 -4.445,-3.073; 2 -3.175,-3.073; 3 -1.905,-3.073; 4 -0.635,-3.073; 5 0.635,-3.073; 6 1.905,-3.073; 7 3.175,-3.073; 8 4.445,-3.073; 9 4.445,3.073; 10 3.175,3.073; 11 1.905,3.073; 12 0.635,3.073; 13 -0.635,3.073; 14 -1.905,3.073; 15 -3.175,3.073; 16 -4.445,3.073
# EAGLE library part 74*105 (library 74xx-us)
Single J-K FLIP FLOP

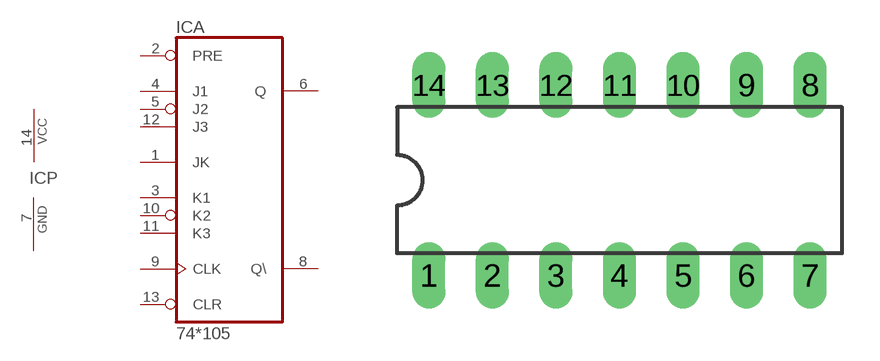
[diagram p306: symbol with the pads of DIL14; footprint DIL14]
Designator prefix IC; gates A=74105 P=PWRN

## 74105N  [DIL14]
1  A:JK  in
2  A:PRE  in
3  A:K1  in
4  A:J1  in
5  A:J2  in
6  A:Q  out
7  P:GND  pwr
8  A:Q\  out
9  A:CLK  in
10  A:K2  in
11  A:K3  in
12  A:J3  in
13  A:CLR  in
14  P:VCC  pwr

## Footprint DIL14 (pad centres in mm)
Dual In Line Package
drill 0.813 long: 1 -7.62,-3.81; 2 -5.08,-3.81; 3 -2.54,-3.81; 4 0,-3.81; 5 2.54,-3.81; 6 5.08,-3.81; 7 7.62,-3.81; 8 7.62,3.81; 9 5.08,3.81; 10 2.54,3.81; 11 0,3.81; 12 -2.54,3.81; 13 -5.08,3.81; 14 -7.62,3.81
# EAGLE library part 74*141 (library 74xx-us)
BCD to decimal DECODER/DRIVER

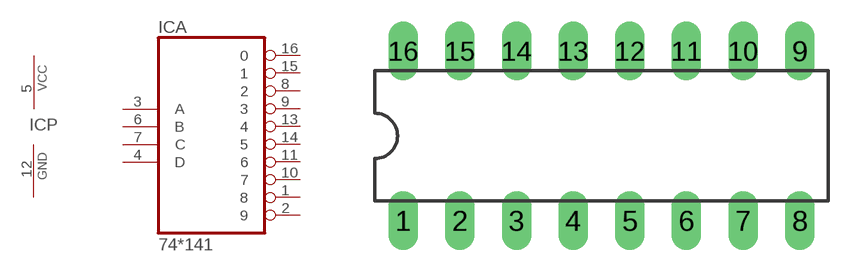
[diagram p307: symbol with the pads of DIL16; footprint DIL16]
Designator prefix IC; gates A=74141 P=PWRN

## 74141N  [DIL16]
1  A:8  oc
2  A:9  oc
3  A:A  in
4  A:D  in
5  P:VCC  pwr
6  A:B  in
7  A:C  in
8  A:2  oc
9  A:3  oc
10  A:7  oc
11  A:6  oc
12  P:GND  pwr
13  A:4  oc
14  A:5  oc
15  A:1  oc
16  A:0  oc

## Footprint DIL16 (pad centres in mm)
Dual In Line Package
drill 0.813 long: 1 -8.89,-3.81; 2 -6.35,-3.81; 3 -3.81,-3.81; 4 -1.27,-3.81; 5 1.27,-3.81; 6 3.81,-3.81; 7 6.35,-3.81; 8 8.89,-3.81; 9 8.89,3.81; 10 6.35,3.81; 11 3.81,3.81; 12 1.27,3.81; 13 -1.27,3.81; 14 -3.81,3.81; 15 -6.35,3.81; 16 -8.89,3.81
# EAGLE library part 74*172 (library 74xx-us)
16-bit multiple port REGISTER, 3-state ouput

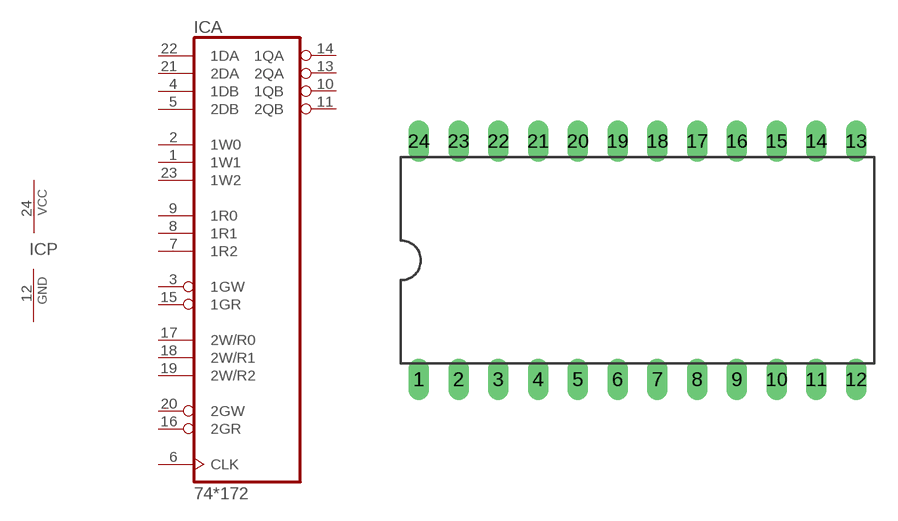
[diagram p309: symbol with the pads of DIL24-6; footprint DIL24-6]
Designator prefix IC; gates A=74172 P=PWRN

## 74172N  [DIL24-6]
1  A:1W1  in
2  A:1W0  in
3  A:1GW  in
4  A:1DB  in
5  A:2DB  in
6  A:CLK  in
7  A:1R2  in
8  A:1R1  in
9  A:1R0  in
10  A:1QB  hiz
11  A:2QB  hiz
12  P:GND  pwr
13  A:2QA  hiz
14  A:1QA  hiz
15  A:1GR  in
16  A:2GR  in
17  A:2W/R0  in
18  A:2W/R1  in
19  A:2W/R2  in
20  A:2GW  in
21  A:2DA  in
22  A:1DA  in
23  A:1W2  in
24  P:VCC  pwr

## Footprint DIL24-6 (pad centres in mm)
Dual In Line Package 0.6 inch
drill 0.813 long: 1 -13.97,-7.62; 2 -11.43,-7.62; 3 -8.89,-7.62; 4 -6.35,-7.62; 5 -3.81,-7.62; 6 -1.27,-7.62; 7 1.27,-7.62; 8 3.81,-7.62; 9 6.35,-7.62; 10 8.89,-7.62; 11 11.43,-7.62; 12 13.97,-7.62; 13 13.97,7.62; 14 11.43,7.62; 15 8.89,7.62; 16 6.35,7.62; 17 3.81,7.62; 18 1.27,7.62; 19 -1.27,7.62; 20 -3.81,7.62; 21 -6.35,7.62; 22 -8.89,7.62; 23 -11.43,7.62; 24 -13.97,7.62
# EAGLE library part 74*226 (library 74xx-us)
4-bit bidirectional BUS DRIVER, buffer

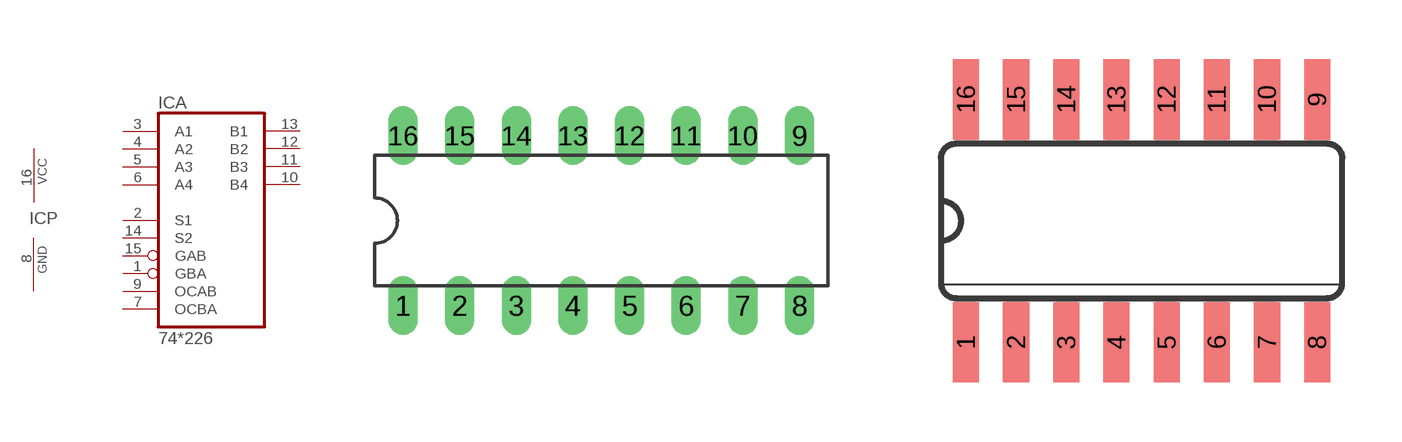
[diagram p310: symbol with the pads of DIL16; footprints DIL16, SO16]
Designator prefix IC; gates A=74226 P=PWRN

## 74S226N  [DIL16]
1  A:GBA  in
2  A:S1  in
3  A:A1  hiz
4  A:A2  hiz
5  A:A3  hiz
6  A:A4  hiz
7  A:OCBA  in
8  P:GND  pwr
9  A:OCAB  in
10  A:B4  hiz
11  A:B3  hiz
12  A:B2  hiz
13  A:B1  hiz
14  A:S2  in
15  A:GAB  in
16  P:VCC  pwr

## 74S226J  [SO16]
Pads as for DIL16

## Footprint DIL16 (pad centres in mm)
Dual In Line Package
drill 0.813 long: 1 -8.89,-3.81; 2 -6.35,-3.81; 3 -3.81,-3.81; 4 -1.27,-3.81; 5 1.27,-3.81; 6 3.81,-3.81; 7 6.35,-3.81; 8 8.89,-3.81; 9 8.89,3.81; 10 6.35,3.81; 11 3.81,3.81; 12 1.27,3.81; 13 -1.27,3.81; 14 -3.81,3.81; 15 -6.35,3.81; 16 -8.89,3.81

## Footprint SO16 (pad centres in mm)
Small Outline package 150 mil
smd 0.66 x 2.032: 1 -4.445,-3.073; 2 -3.175,-3.073; 3 -1.905,-3.073; 4 -0.635,-3.073; 5 0.635,-3.073; 6 1.905,-3.073; 7 3.175,-3.073; 8 4.445,-3.073; 9 4.445,3.073; 10 3.175,3.073; 11 1.905,3.073; 12 0.635,3.073; 13 -0.635,3.073; 14 -1.905,3.073; 15 -3.175,3.073; 16 -4.445,3.073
